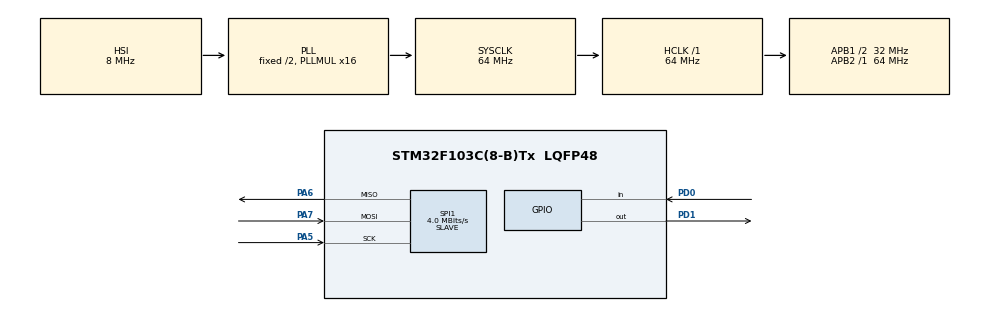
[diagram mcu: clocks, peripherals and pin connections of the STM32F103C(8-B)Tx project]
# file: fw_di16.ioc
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Mcu.Family=STM32F1
Mcu.Name=STM32F103C(8-B)Tx
Mcu.Package=LQFP48
NVIC.PriorityGroup=NVIC_PRIORITYGROUP_4
PA13.Mode=Serial_Wire
PA13.Signal=SYS_JTMS-SWDIO
PA14.Mode=Serial_Wire
PA14.Signal=SYS_JTCK-SWCLK
PA5.Mode=Full_Duplex_Slave
PA5.Signal=SPI1_SCK
PA6.Mode=Full_Duplex_Slave
PA6.Signal=SPI1_MISO
PA7.Mode=Full_Duplex_Slave
PA7.Signal=SPI1_MOSI
PD0-OSC_IN.Signal=GPIO_Input
PD1-OSC_OUT.Signal=GPIO_Output
ProjectManager.HeapSize=0x200
ProjectManager.StackSize=0x400
ProjectManager.TargetToolchain=MDK-ARM V5
RCC.AHBFreq_Value=64000000
RCC.APB1CLKDivider=RCC_HCLK_DIV2
RCC.APB1Freq_Value=32000000
RCC.APB1TimFreq_Value=64000000
RCC.APB2Freq_Value=64000000
RCC.APB2TimFreq_Value=64000000
RCC.HCLKFreq_Value=64000000
RCC.PLLMUL=RCC_PLL_MUL16
RCC.SYSCLKFreq_VALUE=64000000
RCC.SYSCLKSource=RCC_SYSCLKSOURCE_PLLCLK
RCC.USBFreq_Value=64000000
SPI1.BaudRatePrescaler=SPI_BAUDRATEPRESCALER_16
SPI1.CalculateBaudRate=4.0 MBits/s
SPI1.Direction=SPI_DIRECTION_2LINES
SPI1.Mode=SPI_MODE_SLAVE
SPI1.VirtualType=VM_SLAVE
board=fw_di16

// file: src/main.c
/**
  ******************************************************************************
  * File Name          : main.c
  * Description        : Main program body
  ******************************************************************************
  ** This notice applies to any and all portions of this file
  * that are not between comment pairs USER CODE BEGIN and
  * USER CODE END. Other portions of this file, whether
  * inserted by the user or by software development tools
  * are owned by their respective copyright owners.
  *
  * COPYRIGHT(c) 2017 STMicroelectronics
  *
  * Redistribution and use in source and binary forms, with or without modification,
  * are permitted provided that the following conditions are met:
  *   1. Redistributions of source code must retain the above copyright notice,
  *      this list of conditions and the following disclaimer.
  *   2. Redistributions in binary form must reproduce the above copyright notice,
  *      this list of conditions and the following disclaimer in the documentation
  *      and/or other materials provided with the distribution.
  *   3. Neither the name of STMicroelectronics nor the names of its contributors
  *      may be used to endorse or promote products derived from this software
  *      without specific prior written permission.
  *
  * THIS SOFTWARE IS PROVIDED BY THE COPYRIGHT HOLDERS AND CONTRIBUTORS "AS IS"
  * AND ANY EXPRESS OR IMPLIED WARRANTIES, INCLUDING, BUT NOT LIMITED TO, THE
  * IMPLIED WARRANTIES OF MERCHANTABILITY AND FITNESS FOR A PARTICULAR PURPOSE ARE
  * DISCLAIMED. IN NO EVENT SHALL THE COPYRIGHT HOLDER OR CONTRIBUTORS BE LIABLE
  * FOR ANY DIRECT, INDIRECT, INCIDENTAL, SPECIAL, EXEMPLARY, OR CONSEQUENTIAL
  * DAMAGES (INCLUDING, BUT NOT LIMITED TO, PROCUREMENT OF SUBSTITUTE GOODS OR
  * SERVICES; LOSS OF USE, DATA, OR PROFITS; OR BUSINESS INTERRUPTION) HOWEVER
  * CAUSED AND ON ANY THEORY OF LIABILITY, WHETHER IN CONTRACT, STRICT LIABILITY,
  * OR TORT (INCLUDING NEGLIGENCE OR OTHERWISE) ARISING IN ANY WAY OUT OF THE USE
  * OF THIS SOFTWARE, EVEN IF ADVISED OF THE POSSIBILITY OF SUCH DAMAGE.
  *
  ******************************************************************************
  */
#include "main.h"
#include "stm32f1xx_hal.h"

IWDG_HandleTypeDef hiwdg;

SPI_HandleTypeDef hspi1;
DMA_HandleTypeDef hdma_spi1_rx;
DMA_HandleTypeDef hdma_spi1_tx;

/* USER CODE BEGIN PV */
/* Private variables ---------------------------------------------------------*/

/* USER CODE END PV */

void SystemClock_Config(void);
static void MX_GPIO_Init(void);
static void MX_DMA_Init(void);
static void MX_SPI1_Init(void);
static void MX_IWDG_Init(void);

/* USER CODE BEGIN PFP */
/* Private function prototypes -----------------------------------------------*/

/* USER CODE END PFP */

int main(void)
{

  /* MCU Configuration----------------------------------------------------------*/

  /* Reset of all peripherals, Initializes the Flash interface and the Systick. */
  HAL_Init();

  /* Configure the system clock */
  SystemClock_Config();

  /* Initialize all configured peripherals */
  MX_GPIO_Init();
  MX_DMA_Init();
  MX_SPI1_Init();
  MX_IWDG_Init();

  /* Infinite loop */
  while (1)
  {

  }

}

/** System Clock Configuration
*/
void SystemClock_Config(void)
{

  RCC_OscInitTypeDef RCC_OscInitStruct;
  RCC_ClkInitTypeDef RCC_ClkInitStruct;

    /**Initializes the CPU, AHB and APB busses clocks
    */
  RCC_OscInitStruct.OscillatorType = RCC_OSCILLATORTYPE_HSI|RCC_OSCILLATORTYPE_LSI;
  RCC_OscInitStruct.HSIState = RCC_HSI_ON;
  RCC_OscInitStruct.HSICalibrationValue = 16;
  RCC_OscInitStruct.LSIState = RCC_LSI_ON;
  RCC_OscInitStruct.PLL.PLLState = RCC_PLL_ON;
  RCC_OscInitStruct.PLL.PLLSource = RCC_PLLSOURCE_HSI_DIV2;
  RCC_OscInitStruct.PLL.PLLMUL = RCC_PLL_MUL16;
  if (HAL_RCC_OscConfig(&RCC_OscInitStruct) != HAL_OK)
  {
    _Error_Handler(__FILE__, __LINE__);
  }

    /**Initializes the CPU, AHB and APB busses clocks
    */
  RCC_ClkInitStruct.ClockType = RCC_CLOCKTYPE_HCLK|RCC_CLOCKTYPE_SYSCLK
                              |RCC_CLOCKTYPE_PCLK1|RCC_CLOCKTYPE_PCLK2;
  RCC_ClkInitStruct.SYSCLKSource = RCC_SYSCLKSOURCE_PLLCLK;
  RCC_ClkInitStruct.AHBCLKDivider = RCC_SYSCLK_DIV1;
  RCC_ClkInitStruct.APB1CLKDivider = RCC_HCLK_DIV2;
  RCC_ClkInitStruct.APB2CLKDivider = RCC_HCLK_DIV1;

  if (HAL_RCC_ClockConfig(&RCC_ClkInitStruct, FLASH_LATENCY_2) != HAL_OK)
  {
    _Error_Handler(__FILE__, __LINE__);
  }

    /**Configure the Systick interrupt time
    */
  HAL_SYSTICK_Config(HAL_RCC_GetHCLKFreq()/1000);

    /**Configure the Systick
    */
  HAL_SYSTICK_CLKSourceConfig(SYSTICK_CLKSOURCE_HCLK);

  /* SysTick_IRQn interrupt configuration */
  HAL_NVIC_SetPriority(SysTick_IRQn, 0, 0);
}

/* IWDG init function */
static void MX_IWDG_Init(void)
{

  hiwdg.Instance = IWDG;
  hiwdg.Init.Prescaler = IWDG_PRESCALER_4;
  hiwdg.Init.Reload = 4095;
  if (HAL_IWDG_Init(&hiwdg) != HAL_OK)
  {
    _Error_Handler(__FILE__, __LINE__);
  }

}

/* SPI1 init function */
static void MX_SPI1_Init(void)
{

  hspi1.Instance = SPI1;
  hspi1.Init.Mode = SPI_MODE_SLAVE;
  hspi1.Init.Direction = SPI_DIRECTION_2LINES;
  hspi1.Init.DataSize = SPI_DATASIZE_8BIT;
  hspi1.Init.CLKPolarity = SPI_POLARITY_LOW;
  hspi1.Init.CLKPhase = SPI_PHASE_1EDGE;
  hspi1.Init.NSS = SPI_NSS_SOFT;
  hspi1.Init.BaudRatePrescaler = SPI_BAUDRATEPRESCALER_32;
  hspi1.Init.FirstBit = SPI_FIRSTBIT_MSB;
  hspi1.Init.TIMode = SPI_TIMODE_DISABLE;
  hspi1.Init.CRCCalculation = SPI_CRCCALCULATION_DISABLE;
  hspi1.Init.CRCPolynomial = 10;
  if (HAL_SPI_Init(&hspi1) != HAL_OK)
  {
    _Error_Handler(__FILE__, __LINE__);
  }

}

static void MX_DMA_Init(void)
{
  /* DMA controller clock enable */
  __HAL_RCC_DMA1_CLK_ENABLE();

  /* DMA interrupt init */
  /* DMA1_Channel2_IRQn interrupt configuration */
  HAL_NVIC_SetPriority(DMA1_Channel2_IRQn, 0, 0);
  HAL_NVIC_EnableIRQ(DMA1_Channel2_IRQn);
  /* DMA1_Channel3_IRQn interrupt configuration */
  HAL_NVIC_SetPriority(DMA1_Channel3_IRQn, 0, 0);
  HAL_NVIC_EnableIRQ(DMA1_Channel3_IRQn);

}

/** Configure pins as
        * Analog
        * Input
        * Output
        * EVENT_OUT
        * EXTI
        * Free pins are configured automatically as Analog (this feature is enabled through
        * the Code Generation settings)
*/
static void MX_GPIO_Init(void)
{

  GPIO_InitTypeDef GPIO_InitStruct;

  /* GPIO Ports Clock Enable */
  __HAL_RCC_GPIOC_CLK_ENABLE();
  __HAL_RCC_GPIOD_CLK_ENABLE();
  __HAL_RCC_GPIOA_CLK_ENABLE();
  __HAL_RCC_GPIOB_CLK_ENABLE();

  /*Configure GPIO pin Output Level */
  HAL_GPIO_WritePin(SEL_OUT_GPIO_Port, SEL_OUT_Pin, GPIO_PIN_SET);

  /*Configure GPIO pins : DI0_Pin DI1_Pin DI2_Pin */
  GPIO_InitStruct.Pin = DI0_Pin|DI1_Pin|DI2_Pin;
  GPIO_InitStruct.Mode = GPIO_MODE_INPUT;
  GPIO_InitStruct.Pull = GPIO_PULLUP;
  HAL_GPIO_Init(GPIOC, &GPIO_InitStruct);

  /*Configure GPIO pin : SEL_IN_Pin */
  GPIO_InitStruct.Pin = SEL_IN_Pin;
  GPIO_InitStruct.Mode = GPIO_MODE_INPUT;
  GPIO_InitStruct.Pull = GPIO_PULLUP;
  HAL_GPIO_Init(SEL_IN_GPIO_Port, &GPIO_InitStruct);

  /*Configure GPIO pin : SEL_OUT_Pin */
  GPIO_InitStruct.Pin = SEL_OUT_Pin;
  GPIO_InitStruct.Mode = GPIO_MODE_OUTPUT_PP;
  GPIO_InitStruct.Speed = GPIO_SPEED_FREQ_LOW;
  HAL_GPIO_Init(SEL_OUT_GPIO_Port, &GPIO_InitStruct);

  /*Configure GPIO pin : DI3_Pin */
  GPIO_InitStruct.Pin = DI3_Pin;
  GPIO_InitStruct.Mode = GPIO_MODE_INPUT;
  GPIO_InitStruct.Pull = GPIO_NOPULL;
  HAL_GPIO_Init(DI3_GPIO_Port, &GPIO_InitStruct);

  /*Configure GPIO pins : DI4_Pin DI5_Pin DI6_Pin DI7_Pin
                           DI12_Pin DI13_Pin DI14_Pin DI15_Pin */
  GPIO_InitStruct.Pin = DI4_Pin|DI5_Pin|DI6_Pin|DI7_Pin
                          |DI12_Pin|DI13_Pin|DI14_Pin|DI15_Pin;
  GPIO_InitStruct.Mode = GPIO_MODE_INPUT;
  GPIO_InitStruct.Pull = GPIO_PULLUP;
  HAL_GPIO_Init(GPIOA, &GPIO_InitStruct);

  /*Configure GPIO pins : PB0 PB1 PB2 PB10
                           PB11 PB3 PB4 PB5
                           PB6 PB7 PB8 PB9 */
  GPIO_InitStruct.Pin = GPIO_PIN_0|GPIO_PIN_1|GPIO_PIN_2|GPIO_PIN_10
                          |GPIO_PIN_11|GPIO_PIN_3|GPIO_PIN_4|GPIO_PIN_5
                          |GPIO_PIN_6|GPIO_PIN_7|GPIO_PIN_8|GPIO_PIN_9;
  GPIO_InitStruct.Mode = GPIO_MODE_ANALOG;
  HAL_GPIO_Init(GPIOB, &GPIO_InitStruct);

  /*Configure GPIO pins : DI8_Pin DI9_Pin DI10_Pin DI11_Pin */
  GPIO_InitStruct.Pin = DI8_Pin|DI9_Pin|DI10_Pin|DI11_Pin;
  GPIO_InitStruct.Mode = GPIO_MODE_INPUT;
  GPIO_InitStruct.Pull = GPIO_PULLUP;
  HAL_GPIO_Init(GPIOB, &GPIO_InitStruct);

  /*Configure GPIO pins : PA12 PA15 */
  GPIO_InitStruct.Pin = GPIO_PIN_12|GPIO_PIN_15;
  GPIO_InitStruct.Mode = GPIO_MODE_ANALOG;
  HAL_GPIO_Init(GPIOA, &GPIO_InitStruct);

  /*Configure peripheral I/O remapping */
  __HAL_AFIO_REMAP_PD01_ENABLE();

}

void _Error_Handler(char * file, int line)
{
  while(1)
  {
  }
}

/************************ (C) COPYRIGHT STMicroelectronics *****END OF FILE****/
